VERSION 5.8 ;
BUSBITCHARS "[]" ;
DIVIDERCHAR "/" ;
UNITS
    DATABASE MICRONS 1000 ;
END UNITS

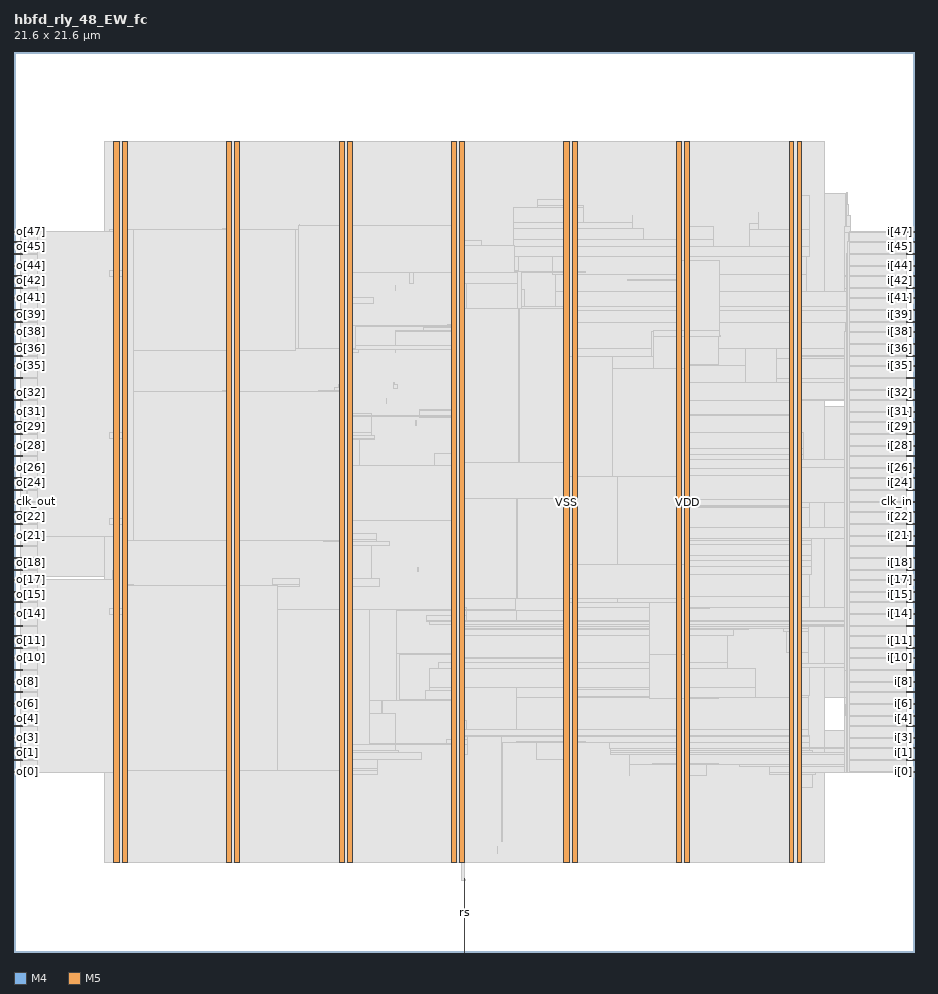
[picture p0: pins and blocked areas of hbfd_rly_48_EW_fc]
MACRO hbfd_rly_48_EW_fc
  FOREIGN hbfd_rly_48_EW_fc 0 0 ;
  CLASS BLOCK ;
  SIZE 21.6 BY 21.6 ;
  PIN clk_in
    DIRECTION INPUT ;
    USE SIGNAL ;
    PORT
      LAYER M4 ;
        RECT  21.408 10.8 21.6 10.824 ;
    END
  END clk_in
  PIN clk_out
    DIRECTION OUTPUT ;
    USE SIGNAL ;
    PORT
      LAYER M4 ;
        RECT  0 10.8 0.192 10.824 ;
    END
  END clk_out
  PIN i[0]
    DIRECTION INPUT ;
    USE SIGNAL ;
    PORT
      LAYER M4 ;
        RECT  21.408 4.32 21.6 4.344 ;
    END
  END i[0]
  PIN i[10]
    DIRECTION INPUT ;
    USE SIGNAL ;
    PORT
      LAYER M4 ;
        RECT  21.408 7.056 21.6 7.08 ;
    END
  END i[10]
  PIN i[11]
    DIRECTION INPUT ;
    USE SIGNAL ;
    PORT
      LAYER M4 ;
        RECT  21.408 7.296 21.6 7.32 ;
    END
  END i[11]
  PIN i[12]
    DIRECTION INPUT ;
    USE SIGNAL ;
    PORT
      LAYER M4 ;
        RECT  21.408 7.584 21.6 7.608 ;
    END
  END i[12]
  PIN i[13]
    DIRECTION INPUT ;
    USE SIGNAL ;
    PORT
      LAYER M4 ;
        RECT  21.408 7.824 21.6 7.848 ;
    END
  END i[13]
  PIN i[14]
    DIRECTION INPUT ;
    USE SIGNAL ;
    PORT
      LAYER M4 ;
        RECT  21.408 8.112 21.6 8.136 ;
    END
  END i[14]
  PIN i[15]
    DIRECTION INPUT ;
    USE SIGNAL ;
    PORT
      LAYER M4 ;
        RECT  21.408 8.4 21.6 8.424 ;
    END
  END i[15]
  PIN i[16]
    DIRECTION INPUT ;
    USE SIGNAL ;
    PORT
      LAYER M4 ;
        RECT  21.408 8.64 21.6 8.664 ;
    END
  END i[16]
  PIN i[17]
    DIRECTION INPUT ;
    USE SIGNAL ;
    PORT
      LAYER M4 ;
        RECT  21.408 8.928 21.6 8.952 ;
    END
  END i[17]
  PIN i[18]
    DIRECTION INPUT ;
    USE SIGNAL ;
    PORT
      LAYER M4 ;
        RECT  21.408 9.168 21.6 9.192 ;
    END
  END i[18]
  PIN i[19]
    DIRECTION INPUT ;
    USE SIGNAL ;
    PORT
      LAYER M4 ;
        RECT  21.408 9.456 21.6 9.48 ;
    END
  END i[19]
  PIN i[1]
    DIRECTION INPUT ;
    USE SIGNAL ;
    PORT
      LAYER M4 ;
        RECT  21.408 4.608 21.6 4.632 ;
    END
  END i[1]
  PIN i[20]
    DIRECTION INPUT ;
    USE SIGNAL ;
    PORT
      LAYER M4 ;
        RECT  21.408 9.744 21.6 9.768 ;
    END
  END i[20]
  PIN i[21]
    DIRECTION INPUT ;
    USE SIGNAL ;
    PORT
      LAYER M4 ;
        RECT  21.408 9.984 21.6 10.008 ;
    END
  END i[21]
  PIN i[22]
    DIRECTION INPUT ;
    USE SIGNAL ;
    PORT
      LAYER M4 ;
        RECT  21.408 10.272 21.6 10.296 ;
    END
  END i[22]
  PIN i[23]
    DIRECTION INPUT ;
    USE SIGNAL ;
    PORT
      LAYER M4 ;
        RECT  21.408 10.56 21.6 10.584 ;
    END
  END i[23]
  PIN i[24]
    DIRECTION INPUT ;
    USE SIGNAL ;
    PORT
      LAYER M4 ;
        RECT  21.408 11.088 21.6 11.112 ;
    END
  END i[24]
  PIN i[25]
    DIRECTION INPUT ;
    USE SIGNAL ;
    PORT
      LAYER M4 ;
        RECT  21.408 11.376 21.6 11.4 ;
    END
  END i[25]
  PIN i[26]
    DIRECTION INPUT ;
    USE SIGNAL ;
    PORT
      LAYER M4 ;
        RECT  21.408 11.616 21.6 11.64 ;
    END
  END i[26]
  PIN i[27]
    DIRECTION INPUT ;
    USE SIGNAL ;
    PORT
      LAYER M4 ;
        RECT  21.408 11.904 21.6 11.928 ;
    END
  END i[27]
  PIN i[28]
    DIRECTION INPUT ;
    USE SIGNAL ;
    PORT
      LAYER M4 ;
        RECT  21.408 12.144 21.6 12.168 ;
    END
  END i[28]
  PIN i[29]
    DIRECTION INPUT ;
    USE SIGNAL ;
    PORT
      LAYER M4 ;
        RECT  21.408 12.432 21.6 12.456 ;
    END
  END i[29]
  PIN i[2]
    DIRECTION INPUT ;
    USE SIGNAL ;
    PORT
      LAYER M4 ;
        RECT  21.408 4.896 21.6 4.92 ;
    END
  END i[2]
  PIN i[30]
    DIRECTION INPUT ;
    USE SIGNAL ;
    PORT
      LAYER M4 ;
        RECT  21.408 12.72 21.6 12.744 ;
    END
  END i[30]
  PIN i[31]
    DIRECTION INPUT ;
    USE SIGNAL ;
    PORT
      LAYER M4 ;
        RECT  21.408 12.96 21.6 12.984 ;
    END
  END i[31]
  PIN i[32]
    DIRECTION INPUT ;
    USE SIGNAL ;
    PORT
      LAYER M4 ;
        RECT  21.408 13.248 21.6 13.272 ;
    END
  END i[32]
  PIN i[33]
    DIRECTION INPUT ;
    USE SIGNAL ;
    PORT
      LAYER M4 ;
        RECT  21.408 13.488 21.6 13.512 ;
    END
  END i[33]
  PIN i[34]
    DIRECTION INPUT ;
    USE SIGNAL ;
    PORT
      LAYER M4 ;
        RECT  21.408 13.776 21.6 13.8 ;
    END
  END i[34]
  PIN i[35]
    DIRECTION INPUT ;
    USE SIGNAL ;
    PORT
      LAYER M4 ;
        RECT  21.408 14.064 21.6 14.088 ;
    END
  END i[35]
  PIN i[36]
    DIRECTION INPUT ;
    USE SIGNAL ;
    PORT
      LAYER M4 ;
        RECT  21.408 14.304 21.6 14.328 ;
    END
  END i[36]
  PIN i[37]
    DIRECTION INPUT ;
    USE SIGNAL ;
    PORT
      LAYER M4 ;
        RECT  21.408 14.592 21.6 14.616 ;
    END
  END i[37]
  PIN i[38]
    DIRECTION INPUT ;
    USE SIGNAL ;
    PORT
      LAYER M4 ;
        RECT  21.408 14.88 21.6 14.904 ;
    END
  END i[38]
  PIN i[39]
    DIRECTION INPUT ;
    USE SIGNAL ;
    PORT
      LAYER M4 ;
        RECT  21.408 15.12 21.6 15.144 ;
    END
  END i[39]
  PIN i[3]
    DIRECTION INPUT ;
    USE SIGNAL ;
    PORT
      LAYER M4 ;
        RECT  21.408 5.136 21.6 5.16 ;
    END
  END i[3]
  PIN i[40]
    DIRECTION INPUT ;
    USE SIGNAL ;
    PORT
      LAYER M4 ;
        RECT  21.408 15.408 21.6 15.432 ;
    END
  END i[40]
  PIN i[41]
    DIRECTION INPUT ;
    USE SIGNAL ;
    PORT
      LAYER M4 ;
        RECT  21.408 15.696 21.6 15.72 ;
    END
  END i[41]
  PIN i[42]
    DIRECTION INPUT ;
    USE SIGNAL ;
    PORT
      LAYER M4 ;
        RECT  21.408 15.936 21.6 15.96 ;
    END
  END i[42]
  PIN i[43]
    DIRECTION INPUT ;
    USE SIGNAL ;
    PORT
      LAYER M4 ;
        RECT  21.408 16.224 21.6 16.248 ;
    END
  END i[43]
  PIN i[44]
    DIRECTION INPUT ;
    USE SIGNAL ;
    PORT
      LAYER M4 ;
        RECT  21.408 16.464 21.6 16.488 ;
    END
  END i[44]
  PIN i[45]
    DIRECTION INPUT ;
    USE SIGNAL ;
    PORT
      LAYER M4 ;
        RECT  21.408 16.752 21.6 16.776 ;
    END
  END i[45]
  PIN i[46]
    DIRECTION INPUT ;
    USE SIGNAL ;
    PORT
      LAYER M4 ;
        RECT  21.408 17.04 21.6 17.064 ;
    END
  END i[46]
  PIN i[47]
    DIRECTION INPUT ;
    USE SIGNAL ;
    PORT
      LAYER M4 ;
        RECT  21.408 17.28 21.6 17.304 ;
    END
  END i[47]
  PIN i[4]
    DIRECTION INPUT ;
    USE SIGNAL ;
    PORT
      LAYER M4 ;
        RECT  21.408 5.424 21.6 5.448 ;
    END
  END i[4]
  PIN i[5]
    DIRECTION INPUT ;
    USE SIGNAL ;
    PORT
      LAYER M4 ;
        RECT  21.408 5.664 21.6 5.688 ;
    END
  END i[5]
  PIN i[6]
    DIRECTION INPUT ;
    USE SIGNAL ;
    PORT
      LAYER M4 ;
        RECT  21.408 5.952 21.6 5.976 ;
    END
  END i[6]
  PIN i[7]
    DIRECTION INPUT ;
    USE SIGNAL ;
    PORT
      LAYER M4 ;
        RECT  21.408 6.24 21.6 6.264 ;
    END
  END i[7]
  PIN i[8]
    DIRECTION INPUT ;
    USE SIGNAL ;
    PORT
      LAYER M4 ;
        RECT  21.408 6.48 21.6 6.504 ;
    END
  END i[8]
  PIN i[9]
    DIRECTION INPUT ;
    USE SIGNAL ;
    PORT
      LAYER M4 ;
        RECT  21.408 6.768 21.6 6.792 ;
    END
  END i[9]
  PIN o[0]
    DIRECTION OUTPUT ;
    USE SIGNAL ;
    PORT
      LAYER M4 ;
        RECT  0 4.32 0.192 4.344 ;
    END
  END o[0]
  PIN o[10]
    DIRECTION OUTPUT ;
    USE SIGNAL ;
    PORT
      LAYER M4 ;
        RECT  0 7.056 0.192 7.08 ;
    END
  END o[10]
  PIN o[11]
    DIRECTION OUTPUT ;
    USE SIGNAL ;
    PORT
      LAYER M4 ;
        RECT  0 7.296 0.192 7.32 ;
    END
  END o[11]
  PIN o[12]
    DIRECTION OUTPUT ;
    USE SIGNAL ;
    PORT
      LAYER M4 ;
        RECT  0 7.584 0.192 7.608 ;
    END
  END o[12]
  PIN o[13]
    DIRECTION OUTPUT ;
    USE SIGNAL ;
    PORT
      LAYER M4 ;
        RECT  0 7.824 0.192 7.848 ;
    END
  END o[13]
  PIN o[14]
    DIRECTION OUTPUT ;
    USE SIGNAL ;
    PORT
      LAYER M4 ;
        RECT  0 8.112 0.192 8.136 ;
    END
  END o[14]
  PIN o[15]
    DIRECTION OUTPUT ;
    USE SIGNAL ;
    PORT
      LAYER M4 ;
        RECT  0 8.4 0.192 8.424 ;
    END
  END o[15]
  PIN o[16]
    DIRECTION OUTPUT ;
    USE SIGNAL ;
    PORT
      LAYER M4 ;
        RECT  0 8.64 0.192 8.664 ;
    END
  END o[16]
  PIN o[17]
    DIRECTION OUTPUT ;
    USE SIGNAL ;
    PORT
      LAYER M4 ;
        RECT  0 8.928 0.192 8.952 ;
    END
  END o[17]
  PIN o[18]
    DIRECTION OUTPUT ;
    USE SIGNAL ;
    PORT
      LAYER M4 ;
        RECT  0 9.168 0.192 9.192 ;
    END
  END o[18]
  PIN o[19]
    DIRECTION OUTPUT ;
    USE SIGNAL ;
    PORT
      LAYER M4 ;
        RECT  0 9.456 0.192 9.48 ;
    END
  END o[19]
  PIN o[1]
    DIRECTION OUTPUT ;
    USE SIGNAL ;
    PORT
      LAYER M4 ;
        RECT  0 4.608 0.192 4.632 ;
    END
  END o[1]
  PIN o[20]
    DIRECTION OUTPUT ;
    USE SIGNAL ;
    PORT
      LAYER M4 ;
        RECT  0 9.744 0.192 9.768 ;
    END
  END o[20]
  PIN o[21]
    DIRECTION OUTPUT ;
    USE SIGNAL ;
    PORT
      LAYER M4 ;
        RECT  0 9.984 0.192 10.008 ;
    END
  END o[21]
  PIN o[22]
    DIRECTION OUTPUT ;
    USE SIGNAL ;
    PORT
      LAYER M4 ;
        RECT  0 10.272 0.192 10.296 ;
    END
  END o[22]
  PIN o[23]
    DIRECTION OUTPUT ;
    USE SIGNAL ;
    PORT
      LAYER M4 ;
        RECT  0 10.56 0.192 10.584 ;
    END
  END o[23]
  PIN o[24]
    DIRECTION OUTPUT ;
    USE SIGNAL ;
    PORT
      LAYER M4 ;
        RECT  0 11.088 0.192 11.112 ;
    END
  END o[24]
  PIN o[25]
    DIRECTION OUTPUT ;
    USE SIGNAL ;
    PORT
      LAYER M4 ;
        RECT  0 11.376 0.192 11.4 ;
    END
  END o[25]
  PIN o[26]
    DIRECTION OUTPUT ;
    USE SIGNAL ;
    PORT
      LAYER M4 ;
        RECT  0 11.616 0.192 11.64 ;
    END
  END o[26]
  PIN o[27]
    DIRECTION OUTPUT ;
    USE SIGNAL ;
    PORT
      LAYER M4 ;
        RECT  0 11.904 0.192 11.928 ;
    END
  END o[27]
  PIN o[28]
    DIRECTION OUTPUT ;
    USE SIGNAL ;
    PORT
      LAYER M4 ;
        RECT  0 12.144 0.192 12.168 ;
    END
  END o[28]
  PIN o[29]
    DIRECTION OUTPUT ;
    USE SIGNAL ;
    PORT
      LAYER M4 ;
        RECT  0 12.432 0.192 12.456 ;
    END
  END o[29]
  PIN o[2]
    DIRECTION OUTPUT ;
    USE SIGNAL ;
    PORT
      LAYER M4 ;
        RECT  0 4.896 0.192 4.92 ;
    END
  END o[2]
  PIN o[30]
    DIRECTION OUTPUT ;
    USE SIGNAL ;
    PORT
      LAYER M4 ;
        RECT  0 12.72 0.192 12.744 ;
    END
  END o[30]
  PIN o[31]
    DIRECTION OUTPUT ;
    USE SIGNAL ;
    PORT
      LAYER M4 ;
        RECT  0 12.96 0.192 12.984 ;
    END
  END o[31]
  PIN o[32]
    DIRECTION OUTPUT ;
    USE SIGNAL ;
    PORT
      LAYER M4 ;
        RECT  0 13.248 0.192 13.272 ;
    END
  END o[32]
  PIN o[33]
    DIRECTION OUTPUT ;
    USE SIGNAL ;
    PORT
      LAYER M4 ;
        RECT  0 13.488 0.192 13.512 ;
    END
  END o[33]
  PIN o[34]
    DIRECTION OUTPUT ;
    USE SIGNAL ;
    PORT
      LAYER M4 ;
        RECT  0 13.776 0.192 13.8 ;
    END
  END o[34]
  PIN o[35]
    DIRECTION OUTPUT ;
    USE SIGNAL ;
    PORT
      LAYER M4 ;
        RECT  0 14.064 0.192 14.088 ;
    END
  END o[35]
  PIN o[36]
    DIRECTION OUTPUT ;
    USE SIGNAL ;
    PORT
      LAYER M4 ;
        RECT  0 14.304 0.192 14.328 ;
    END
  END o[36]
  PIN o[37]
    DIRECTION OUTPUT ;
    USE SIGNAL ;
    PORT
      LAYER M4 ;
        RECT  0 14.592 0.192 14.616 ;
    END
  END o[37]
  PIN o[38]
    DIRECTION OUTPUT ;
    USE SIGNAL ;
    PORT
      LAYER M4 ;
        RECT  0 14.88 0.192 14.904 ;
    END
  END o[38]
  PIN o[39]
    DIRECTION OUTPUT ;
    USE SIGNAL ;
    PORT
      LAYER M4 ;
        RECT  0 15.12 0.192 15.144 ;
    END
  END o[39]
  PIN o[3]
    DIRECTION OUTPUT ;
    USE SIGNAL ;
    PORT
      LAYER M4 ;
        RECT  0 5.136 0.192 5.16 ;
    END
  END o[3]
  PIN o[40]
    DIRECTION OUTPUT ;
    USE SIGNAL ;
    PORT
      LAYER M4 ;
        RECT  0 15.408 0.192 15.432 ;
    END
  END o[40]
  PIN o[41]
    DIRECTION OUTPUT ;
    USE SIGNAL ;
    PORT
      LAYER M4 ;
        RECT  0 15.696 0.192 15.72 ;
    END
  END o[41]
  PIN o[42]
    DIRECTION OUTPUT ;
    USE SIGNAL ;
    PORT
      LAYER M4 ;
        RECT  0 15.936 0.192 15.96 ;
    END
  END o[42]
  PIN o[43]
    DIRECTION OUTPUT ;
    USE SIGNAL ;
    PORT
      LAYER M4 ;
        RECT  0 16.224 0.192 16.248 ;
    END
  END o[43]
  PIN o[44]
    DIRECTION OUTPUT ;
    USE SIGNAL ;
    PORT
      LAYER M4 ;
        RECT  0 16.464 0.192 16.488 ;
    END
  END o[44]
  PIN o[45]
    DIRECTION OUTPUT ;
    USE SIGNAL ;
    PORT
      LAYER M4 ;
        RECT  0 16.752 0.192 16.776 ;
    END
  END o[45]
  PIN o[46]
    DIRECTION OUTPUT ;
    USE SIGNAL ;
    PORT
      LAYER M4 ;
        RECT  0 17.04 0.192 17.064 ;
    END
  END o[46]
  PIN o[47]
    DIRECTION OUTPUT ;
    USE SIGNAL ;
    PORT
      LAYER M4 ;
        RECT  0 17.28 0.192 17.304 ;
    END
  END o[47]
  PIN o[4]
    DIRECTION OUTPUT ;
    USE SIGNAL ;
    PORT
      LAYER M4 ;
        RECT  0 5.424 0.192 5.448 ;
    END
  END o[4]
  PIN o[5]
    DIRECTION OUTPUT ;
    USE SIGNAL ;
    PORT
      LAYER M4 ;
        RECT  0 5.664 0.192 5.688 ;
    END
  END o[5]
  PIN o[6]
    DIRECTION OUTPUT ;
    USE SIGNAL ;
    PORT
      LAYER M4 ;
        RECT  0 5.952 0.192 5.976 ;
    END
  END o[6]
  PIN o[7]
    DIRECTION OUTPUT ;
    USE SIGNAL ;
    PORT
      LAYER M4 ;
        RECT  0 6.24 0.192 6.264 ;
    END
  END o[7]
  PIN o[8]
    DIRECTION OUTPUT ;
    USE SIGNAL ;
    PORT
      LAYER M4 ;
        RECT  0 6.48 0.192 6.504 ;
    END
  END o[8]
  PIN o[9]
    DIRECTION OUTPUT ;
    USE SIGNAL ;
    PORT
      LAYER M4 ;
        RECT  0 6.768 0.192 6.792 ;
    END
  END o[9]
  PIN rs
    DIRECTION INPUT ;
    USE SIGNAL ;
    PORT
      LAYER M5 ;
        RECT  10.8 0 10.824 0.192 ;
    END
    PORT
      LAYER M5 ;
        RECT  10.8 0.144 10.824 1.763 ;
    END
  END rs
  PIN VDD
    DIRECTION INOUT ;
    USE POWER ;
    PORT
      LAYER M5 ;
        RECT  18.792 2.151 18.912 19.449 ;
        RECT  16.092 2.151 16.212 19.449 ;
        RECT  13.392 2.151 13.512 19.449 ;
        RECT  10.692 2.151 10.812 19.449 ;
        RECT  7.992 2.151 8.112 19.449 ;
        RECT  5.292 2.151 5.412 19.449 ;
        RECT  2.592 2.151 2.712 19.449 ;
    END
  END VDD
  PIN VSS
    DIRECTION INOUT ;
    USE GROUND ;
    PORT
      LAYER M5 ;
        RECT  18.6 2.137 18.72 19.463 ;
        RECT  15.9 2.137 16.02 19.463 ;
        RECT  13.2 2.137 13.32 19.463 ;
        RECT  10.5 2.137 10.62 19.463 ;
        RECT  7.8 2.137 7.92 19.463 ;
        RECT  5.1 2.137 5.22 19.463 ;
        RECT  2.4 2.137 2.52 19.463 ;
    END
  END VSS
  # OT_OBS_CLOSED layer=M5 d_um=1.536 added=10
  OBS
    LAYER RVTN ;
     RECT  2.16 2.16 19.44 2.295 ;
     RECT  2.16 2.565 19.44 2.835 ;
     RECT  2.16 3.105 19.44 3.375 ;
     RECT  2.16 3.645 19.44 3.915 ;
     RECT  2.16 4.185 19.44 4.455 ;
     RECT  2.16 4.725 19.44 4.995 ;
     RECT  2.16 5.265 19.44 5.535 ;
     RECT  2.16 5.805 19.44 6.075 ;
     RECT  2.16 6.345 19.44 6.615 ;
     RECT  2.16 6.885 19.44 7.155 ;
     RECT  2.16 7.425 19.44 7.695 ;
     RECT  2.16 7.965 19.44 8.235 ;
     RECT  2.16 8.505 19.44 8.775 ;
     RECT  2.16 9.045 19.44 9.315 ;
     RECT  2.16 9.585 19.44 9.855 ;
     RECT  2.16 10.125 19.44 10.395 ;
     RECT  2.16 10.665 19.44 10.935 ;
     RECT  2.16 11.205 19.44 11.475 ;
     RECT  2.16 11.745 19.44 12.015 ;
     RECT  2.16 12.285 19.44 12.555 ;
     RECT  2.16 12.825 19.44 13.095 ;
     RECT  2.16 13.365 19.44 13.635 ;
     RECT  2.16 13.905 19.44 14.175 ;
     RECT  2.16 14.445 19.44 14.715 ;
     RECT  2.16 14.985 19.44 15.255 ;
     RECT  2.16 15.525 19.44 15.795 ;
     RECT  2.16 16.065 19.44 16.335 ;
     RECT  2.16 16.605 19.44 16.875 ;
     RECT  2.16 17.145 19.44 17.415 ;
     RECT  2.16 17.685 19.44 17.955 ;
     RECT  2.16 18.225 19.44 18.495 ;
     RECT  2.16 18.765 19.44 19.035 ;
     RECT  2.16 19.305 19.44 19.44 ;
    LAYER RVTP ;
     RECT  2.16 2.295 19.44 2.565 ;
     RECT  2.16 2.835 19.44 3.105 ;
     RECT  2.16 3.375 19.44 3.645 ;
     RECT  2.16 3.915 19.44 4.185 ;
     RECT  2.16 4.455 19.44 4.725 ;
     RECT  2.16 4.995 19.44 5.265 ;
     RECT  2.16 5.535 19.44 5.805 ;
     RECT  2.16 6.075 19.44 6.345 ;
     RECT  2.16 6.615 19.44 6.885 ;
     RECT  2.16 7.155 19.44 7.425 ;
     RECT  2.16 7.695 19.44 7.965 ;
     RECT  2.16 8.235 19.44 8.505 ;
     RECT  2.16 8.775 19.44 9.045 ;
     RECT  2.16 9.315 19.44 9.585 ;
     RECT  2.16 9.855 19.44 10.125 ;
     RECT  2.16 10.395 19.44 10.665 ;
     RECT  2.16 10.935 19.44 11.205 ;
     RECT  2.16 11.475 19.44 11.745 ;
     RECT  2.16 12.015 19.44 12.285 ;
     RECT  2.16 12.555 19.44 12.825 ;
     RECT  2.16 13.095 19.44 13.365 ;
     RECT  2.16 13.635 19.44 13.905 ;
     RECT  2.16 14.175 19.44 14.445 ;
     RECT  2.16 14.715 19.44 14.985 ;
     RECT  2.16 15.255 19.44 15.525 ;
     RECT  2.16 15.795 19.44 16.065 ;
     RECT  2.16 16.335 19.44 16.605 ;
     RECT  2.16 16.875 19.44 17.145 ;
     RECT  2.16 17.415 19.44 17.685 ;
     RECT  2.16 17.955 19.44 18.225 ;
     RECT  2.16 18.495 19.44 18.765 ;
     RECT  2.16 19.035 19.44 19.305 ;
    LAYER M1 ;
     RECT  2.16 2.151 19.44 19.449 ;
    LAYER M2 ;
     RECT  0.211 16.038 0.247 16.056 ;
     RECT  0.211 9.486 0.535 10.314 ;
     RECT  0.211 11.646 0.535 11.664 ;
     RECT  0.211 13.266 0.535 13.932 ;
     RECT  0.211 5.166 2.16 5.724 ;
     RECT  0.211 7.236 2.16 8.262 ;
     RECT  0.535 9.018 2.16 10.314 ;
     RECT  0.535 11.25 2.16 12.384 ;
     RECT  0.535 13.266 2.16 15.246 ;
     RECT  0.247 16.038 2.16 16.794 ;
     RECT  2.16 2.151 19.44 19.449 ;
     RECT  19.44 4.428 19.967 5.328 ;
     RECT  19.44 6.12 19.967 13.086 ;
     RECT  19.44 13.878 19.967 18.216 ;
     RECT  19.967 9.09 20.003 9.648 ;
     RECT  19.967 11.826 20.003 11.844 ;
     RECT  19.967 14.22 20.003 14.238 ;
     RECT  19.967 15.3 20.003 16.668 ;
     RECT  19.967 17.658 20.003 18.216 ;
     RECT  19.967 10.908 20.039 10.926 ;
     RECT  20.003 16.308 20.039 16.326 ;
     RECT  20.003 17.658 20.039 17.946 ;
     RECT  20.039 17.658 20.075 17.676 ;
     RECT  19.967 5.04 20.543 5.058 ;
     RECT  19.967 6.12 20.543 6.84 ;
     RECT  20.003 9.09 20.543 9.108 ;
    LAYER M3 ;
     RECT  10.8 1.723 10.818 2.143 ;
     RECT  10.515 2.143 10.818 2.255 ;
     RECT  2.415 2.143 2.505 2.413 ;
     RECT  5.115 2.143 5.205 2.413 ;
     RECT  7.815 2.143 7.905 2.413 ;
     RECT  13.215 2.143 13.305 2.413 ;
     RECT  15.915 2.143 16.005 2.413 ;
     RECT  18.615 2.143 18.705 2.413 ;
     RECT  11.592 2.371 11.61 2.525 ;
     RECT  18.615 2.413 18.897 3.955 ;
     RECT  15.915 2.413 16.197 4.225 ;
     RECT  7.815 2.413 8.097 4.261 ;
     RECT  18.615 3.955 19.17 4.261 ;
     RECT  2.415 2.413 2.697 4.315 ;
     RECT  18.144 4.261 19.242 4.315 ;
     RECT  5.115 2.413 5.397 4.351 ;
     RECT  7.815 4.261 8.73 4.351 ;
     RECT  7.704 4.351 8.73 4.397 ;
     RECT  18.144 4.315 19.962 4.459 ;
     RECT  15.915 4.225 16.614 4.495 ;
     RECT  17.424 4.459 19.962 4.495 ;
     RECT  14.76 4.225 14.778 4.507 ;
     RECT  15.915 4.495 19.962 4.507 ;
     RECT  7.815 4.397 8.73 4.621 ;
     RECT  13.215 2.413 13.497 4.621 ;
     RECT  10.515 2.255 10.797 4.729 ;
     RECT  14.76 4.507 19.962 4.729 ;
     RECT  7.815 4.621 9.774 4.793 ;
     RECT  14.328 4.729 19.962 4.793 ;
     RECT  7.815 4.793 9.234 4.829 ;
     RECT  14.328 4.793 19.17 4.829 ;
     RECT  14.328 4.829 19.098 4.891 ;
     RECT  2.304 4.315 2.697 4.928 ;
     RECT  5.004 4.351 5.397 4.928 ;
     RECT  10.515 4.729 10.89 4.987 ;
     RECT  6.84 4.891 6.858 5.021 ;
     RECT  12.528 4.621 13.497 5.029 ;
     RECT  14.292 4.891 19.098 5.029 ;
     RECT  11.7 2.641 11.718 5.032 ;
     RECT  12.528 5.029 19.098 5.032 ;
     RECT  19.944 4.793 19.962 5.035 ;
     RECT  10.368 4.987 10.89 5.099 ;
     RECT  10.515 5.099 10.89 5.161 ;
     RECT  11.7 5.032 19.098 5.161 ;
     RECT  19.944 5.035 20.538 5.165 ;
     RECT  10.515 5.161 19.098 5.189 ;
     RECT  10.515 5.189 19.062 5.333 ;
     RECT  0.216 5.131 0.234 5.563 ;
     RECT  10.515 5.333 10.854 5.567 ;
     RECT  0.216 5.563 0.27 5.693 ;
     RECT  0.216 5.693 0.234 5.729 ;
     RECT  7.815 4.829 9.162 5.729 ;
     RECT  7.056 5.701 7.074 5.809 ;
     RECT  6.768 5.809 7.074 5.873 ;
     RECT  6.768 5.873 6.858 5.909 ;
     RECT  2.415 4.928 2.697 5.947 ;
     RECT  19.944 5.165 19.962 5.947 ;
     RECT  10.515 5.567 10.797 6.043 ;
     RECT  12.06 5.333 19.062 6.107 ;
     RECT  19.944 5.947 19.998 6.115 ;
     RECT  2.304 5.947 2.697 6.139 ;
     RECT  5.115 4.928 5.397 6.139 ;
     RECT  18.615 6.107 19.062 6.151 ;
     RECT  6.84 5.909 6.858 6.173 ;
     RECT  5.115 6.139 5.49 6.179 ;
     RECT  9.864 6.043 10.797 6.269 ;
     RECT  9.972 6.269 10.797 6.349 ;
     RECT  12.06 6.107 17.802 6.349 ;
     RECT  2.304 6.139 2.79 6.523 ;
     RECT  7.815 5.729 8.097 6.619 ;
     RECT  2.304 6.523 2.862 6.653 ;
     RECT  7.704 6.619 8.097 6.655 ;
     RECT  8.82 5.729 8.838 6.691 ;
     RECT  7.596 6.655 8.097 6.781 ;
     RECT  8.82 6.691 9.126 6.781 ;
     RECT  7.596 6.781 9.234 6.809 ;
     RECT  9.972 6.349 17.802 6.809 ;
     RECT  18.615 6.151 19.098 6.817 ;
     RECT  19.944 6.115 20.538 6.817 ;
     RECT  9.108 6.809 9.234 6.845 ;
     RECT  9.216 6.845 9.234 6.893 ;
     RECT  18.615 6.817 20.538 6.917 ;
     RECT  10.188 6.809 17.118 6.953 ;
     RECT  5.115 6.179 5.397 7.051 ;
     RECT  19.944 6.917 20.538 7.085 ;
     RECT  2.304 6.653 2.697 7.088 ;
     RECT  5.004 7.051 5.397 7.088 ;
     RECT  18.615 6.917 19.062 7.195 ;
     RECT  10.515 6.953 17.118 7.591 ;
     RECT  5.115 7.088 5.397 7.699 ;
     RECT  7.815 6.809 8.19 7.699 ;
     RECT  18.54 7.195 19.062 7.699 ;
     RECT  10.515 7.591 17.262 7.735 ;
     RECT  10.515 7.735 17.622 7.771 ;
     RECT  18.468 7.699 19.062 7.771 ;
     RECT  5.115 7.699 5.922 7.799 ;
     RECT  10.515 7.771 19.062 7.819 ;
     RECT  19.944 7.085 19.962 7.819 ;
     RECT  2.415 7.088 2.697 7.861 ;
     RECT  10.515 7.819 19.962 7.861 ;
     RECT  7.815 7.699 8.766 7.889 ;
     RECT  2.415 7.861 2.79 7.901 ;
     RECT  5.115 7.799 5.49 7.901 ;
     RECT  9.972 7.861 19.962 7.933 ;
     RECT  9.9 7.933 19.962 7.961 ;
     RECT  6.84 7.051 6.858 7.997 ;
     RECT  9.144 7.897 9.162 7.997 ;
     RECT  9.9 7.961 10.854 8.069 ;
     RECT  10.515 8.069 10.854 8.267 ;
     RECT  12.06 7.961 19.962 8.267 ;
     RECT  0.216 7.231 0.234 8.429 ;
     RECT  12.06 8.267 19.098 8.525 ;
     RECT  12.06 8.525 15.03 8.537 ;
     RECT  2.415 7.901 2.697 8.635 ;
     RECT  2.304 8.635 2.697 8.683 ;
     RECT  2.304 8.683 2.862 8.699 ;
     RECT  7.815 7.889 8.097 8.779 ;
     RECT  2.376 8.699 2.862 8.813 ;
     RECT  6.3 8.779 6.858 8.815 ;
     RECT  19.944 8.267 19.962 8.923 ;
     RECT  6.192 8.815 6.858 8.969 ;
     RECT  7.815 8.779 8.766 8.969 ;
     RECT  15.876 8.525 19.098 9.049 ;
     RECT  19.944 8.923 19.998 9.085 ;
     RECT  2.376 8.813 2.697 9.149 ;
     RECT  0.54 9.013 0.558 9.197 ;
     RECT  19.944 9.085 20.538 9.197 ;
     RECT  10.515 8.267 10.797 9.211 ;
     RECT  9.684 9.121 9.702 9.239 ;
     RECT  12.564 8.537 15.03 9.259 ;
     RECT  15.876 9.049 19.134 9.259 ;
     RECT  10.515 9.211 11.43 9.311 ;
     RECT  12.564 9.259 19.134 9.391 ;
     RECT  10.515 9.311 10.962 9.509 ;
     RECT  11.952 9.391 19.134 9.509 ;
     RECT  7.815 8.969 8.586 9.751 ;
     RECT  11.988 9.509 19.134 9.779 ;
     RECT  7.815 9.751 9.018 9.851 ;
     RECT  7.815 9.851 8.694 9.859 ;
     RECT  2.415 9.149 2.697 9.883 ;
     RECT  12.564 9.779 19.134 9.887 ;
     RECT  7.416 9.859 8.694 9.895 ;
     RECT  12.852 9.887 19.134 9.931 ;
     RECT  19.944 9.197 20.034 9.931 ;
     RECT  7.164 9.895 8.694 10.049 ;
     RECT  2.415 9.883 2.862 10.061 ;
     RECT  7.308 10.049 8.097 10.121 ;
     RECT  12.852 9.931 20.034 10.193 ;
     RECT  10.515 9.509 10.854 10.291 ;
     RECT  10.515 10.291 11.502 10.463 ;
     RECT  10.515 10.463 11.214 10.499 ;
     RECT  12.852 10.193 19.098 10.661 ;
     RECT  12.852 10.661 13.497 10.741 ;
     RECT  12.672 10.741 13.497 10.843 ;
     RECT  12.06 10.843 13.497 10.859 ;
     RECT  14.22 10.661 19.098 10.859 ;
     RECT  12.06 10.859 12.078 10.931 ;
     RECT  19.944 10.193 20.034 10.931 ;
     RECT  7.815 10.121 8.097 10.975 ;
     RECT  12.852 10.859 13.497 11.003 ;
     RECT  7.815 10.975 8.586 11.129 ;
     RECT  10.515 10.499 11.034 11.165 ;
     RECT  10.515 11.165 10.926 11.209 ;
     RECT  0.216 9.451 0.234 11.245 ;
     RECT  7.815 11.129 8.478 11.309 ;
     RECT  12.888 11.003 13.497 11.443 ;
     RECT  14.22 10.859 19.062 11.443 ;
     RECT  10.224 11.209 10.926 11.515 ;
     RECT  12.888 11.443 19.062 11.611 ;
     RECT  19.944 10.931 19.962 11.611 ;
     RECT  0.216 11.245 0.558 11.669 ;
     RECT  12.06 11.749 12.078 11.789 ;
     RECT  12.888 11.611 19.962 11.813 ;
     RECT  12.888 11.813 18.954 11.821 ;
     RECT  19.944 11.813 19.962 11.821 ;
     RECT  0.252 11.669 0.558 11.933 ;
     RECT  12.276 11.821 18.954 11.939 ;
     RECT  10.08 11.515 10.926 11.975 ;
     RECT  10.515 11.975 10.926 12.019 ;
     RECT  14.58 11.939 18.954 12.083 ;
     RECT  10.515 12.019 11.466 12.119 ;
     RECT  19.944 11.821 19.998 12.173 ;
     RECT  2.415 10.061 2.697 12.181 ;
     RECT  5.115 7.901 5.397 12.217 ;
     RECT  2.415 12.181 2.79 12.289 ;
     RECT  7.815 11.309 8.298 12.289 ;
     RECT  6.732 12.325 6.75 12.331 ;
     RECT  7.815 12.289 8.658 12.331 ;
     RECT  2.415 12.289 2.862 12.389 ;
     RECT  5.115 12.217 5.67 12.389 ;
     RECT  6.732 12.331 8.658 12.389 ;
     RECT  6.732 12.389 8.586 12.479 ;
     RECT  14.652 12.083 18.954 12.479 ;
     RECT  0.54 11.933 0.558 12.749 ;
     RECT  9.648 12.631 9.666 12.749 ;
     RECT  10.515 12.119 10.854 12.829 ;
     RECT  12.276 11.939 13.698 12.829 ;
     RECT  12.06 12.829 13.698 12.865 ;
     RECT  14.652 12.479 18.897 12.865 ;
     RECT  12.06 12.865 18.897 12.893 ;
     RECT  6.84 12.479 8.586 12.929 ;
     RECT  2.415 12.389 2.697 12.955 ;
     RECT  5.115 12.389 5.397 12.991 ;
     RECT  9.72 12.829 10.854 12.991 ;
     RECT  9.72 12.991 11.07 13.019 ;
     RECT  6.84 12.929 8.097 13.037 ;
     RECT  12.24 12.893 18.897 13.243 ;
     RECT  19.944 12.173 19.962 13.243 ;
     RECT  8.928 13.171 8.946 13.289 ;
     RECT  5.004 12.991 5.397 13.469 ;
     RECT  7.308 13.037 8.097 13.469 ;
     RECT  2.304 12.955 2.697 13.517 ;
     RECT  7.704 13.469 8.097 13.559 ;
     RECT  0.216 13.243 0.234 13.603 ;
     RECT  7.776 13.559 8.097 13.631 ;
     RECT  9.108 13.531 9.198 13.631 ;
     RECT  9.108 13.631 9.126 13.667 ;
     RECT  12.24 13.243 19.962 13.667 ;
     RECT  18.288 13.667 19.962 13.771 ;
     RECT  10.515 13.019 11.07 13.801 ;
     RECT  0.216 13.603 0.558 13.805 ;
     RECT  10.515 13.801 11.286 14.009 ;
     RECT  12.24 13.667 17.55 14.071 ;
     RECT  18.288 13.771 19.998 14.243 ;
     RECT  2.415 13.517 2.697 14.341 ;
     RECT  2.415 14.341 2.79 14.347 ;
     RECT  7.815 13.631 8.097 14.377 ;
     RECT  7.815 14.377 8.262 14.449 ;
     RECT  9.144 14.377 9.162 14.449 ;
     RECT  10.515 14.009 10.797 14.449 ;
     RECT  2.415 14.347 2.862 14.477 ;
     RECT  11.52 14.071 17.55 14.477 ;
     RECT  12.348 14.477 17.55 14.485 ;
     RECT  18.288 14.243 19.962 14.485 ;
     RECT  6.732 14.443 6.75 14.549 ;
     RECT  7.815 14.449 10.797 14.549 ;
     RECT  0.216 13.805 0.234 14.611 ;
     RECT  0.216 14.611 0.558 14.621 ;
     RECT  9.144 14.549 10.797 14.881 ;
     RECT  9.144 14.881 11.322 14.909 ;
     RECT  9.828 14.909 11.322 14.981 ;
     RECT  6.84 14.611 6.858 15.019 ;
     RECT  10.404 14.981 10.854 15.053 ;
     RECT  2.415 14.477 2.697 15.115 ;
     RECT  12.348 14.485 19.962 15.115 ;
     RECT  5.115 13.469 5.397 15.151 ;
     RECT  6.84 15.019 6.894 15.151 ;
     RECT  7.815 14.549 8.097 15.151 ;
     RECT  2.304 15.115 2.697 15.223 ;
     RECT  6.84 15.151 8.097 15.251 ;
     RECT  6.84 15.251 6.858 15.287 ;
     RECT  2.304 15.223 2.862 15.359 ;
     RECT  12.348 15.115 19.998 15.403 ;
     RECT  0.54 14.621 0.558 15.437 ;
     RECT  12.096 15.403 19.998 15.485 ;
     RECT  7.704 15.251 8.097 15.565 ;
     RECT  7.704 15.565 8.622 15.719 ;
     RECT  7.704 15.719 8.097 15.725 ;
     RECT  2.304 15.359 2.697 15.728 ;
     RECT  5.004 15.151 5.397 15.728 ;
     RECT  12.996 15.485 19.998 15.863 ;
     RECT  12.096 15.485 12.258 15.899 ;
     RECT  19.944 15.863 19.998 15.931 ;
     RECT  9.144 15.871 9.162 15.989 ;
     RECT  10.515 15.053 10.854 16.033 ;
     RECT  12.096 15.899 12.114 16.033 ;
     RECT  0.216 15.931 0.234 16.061 ;
     RECT  12.996 15.863 19.026 16.267 ;
     RECT  10.515 16.033 12.114 16.367 ;
     RECT  2.415 15.728 2.697 16.501 ;
     RECT  5.115 15.728 5.397 16.501 ;
     RECT  9.504 16.033 9.594 16.573 ;
     RECT  11.988 16.367 12.114 16.681 ;
     RECT  12.924 16.267 19.026 16.681 ;
     RECT  0.252 16.747 0.27 16.799 ;
     RECT  9.504 16.573 9.666 16.799 ;
     RECT  11.988 16.681 19.098 16.943 ;
     RECT  2.415 16.501 2.79 16.979 ;
     RECT  5.115 16.501 5.49 16.979 ;
     RECT  9.324 16.915 9.414 17.069 ;
     RECT  10.515 16.367 11.214 17.069 ;
     RECT  11.988 16.943 16.794 17.105 ;
     RECT  9.396 17.069 9.414 17.213 ;
     RECT  2.415 16.979 2.697 17.275 ;
     RECT  19.944 15.931 20.034 17.275 ;
     RECT  5.115 16.979 5.397 17.311 ;
     RECT  2.304 17.275 2.697 17.339 ;
     RECT  17.64 16.943 19.098 17.339 ;
     RECT  5.004 17.311 5.397 17.357 ;
     RECT  11.988 17.105 15.102 17.375 ;
     RECT  15.915 17.105 16.794 17.411 ;
     RECT  19.944 17.275 20.07 17.411 ;
     RECT  10.515 17.069 10.797 17.419 ;
     RECT  6.84 17.323 6.858 17.453 ;
     RECT  17.64 17.339 17.874 17.483 ;
     RECT  10.512 17.419 10.797 17.519 ;
     RECT  11.988 17.375 14.85 17.519 ;
     RECT  14.832 17.519 14.85 17.681 ;
     RECT  19.98 17.411 20.07 17.681 ;
     RECT  17.856 17.483 17.874 17.753 ;
     RECT  11.988 17.519 13.662 17.879 ;
     RECT  12.564 17.879 13.662 17.915 ;
     RECT  19.98 17.681 20.034 17.951 ;
     RECT  12.564 17.915 13.497 18.059 ;
     RECT  18.615 17.339 19.098 18.149 ;
     RECT  19.98 17.951 19.998 18.221 ;
     RECT  2.415 17.339 2.697 19.187 ;
     RECT  5.115 17.357 5.397 19.187 ;
     RECT  7.815 15.725 8.097 19.187 ;
     RECT  10.515 17.519 10.797 19.187 ;
     RECT  13.215 18.059 13.497 19.187 ;
     RECT  15.915 17.411 16.197 19.187 ;
     RECT  18.615 18.149 18.897 19.187 ;
     RECT  2.415 19.187 2.505 19.457 ;
     RECT  5.115 19.187 5.205 19.457 ;
     RECT  7.815 19.187 7.905 19.457 ;
     RECT  10.515 19.187 10.605 19.457 ;
     RECT  13.215 19.187 13.305 19.457 ;
     RECT  15.915 19.187 16.005 19.457 ;
     RECT  18.615 19.187 18.705 19.457 ;
    LAYER M4 ;
     RECT  0.192 4.32 0.569 4.344 ;
     RECT  0.156 4.344 0.569 4.608 ;
     RECT  0.192 4.608 0.569 4.632 ;
     RECT  0.156 4.632 0.569 4.896 ;
     RECT  0.192 4.896 0.569 4.92 ;
     RECT  0.156 4.92 0.569 5.136 ;
     RECT  0.192 5.136 0.569 5.16 ;
     RECT  0.156 5.16 0.569 5.424 ;
     RECT  0.192 5.424 0.569 5.448 ;
     RECT  0.156 5.448 0.569 5.664 ;
     RECT  0.192 5.664 0.569 5.688 ;
     RECT  0.156 5.688 0.569 5.952 ;
     RECT  0.192 5.952 0.569 5.976 ;
     RECT  0.156 5.976 0.569 6.24 ;
     RECT  0.192 6.24 0.569 6.264 ;
     RECT  0.156 6.264 0.569 6.48 ;
     RECT  0.192 6.48 0.569 6.504 ;
     RECT  0.156 6.504 0.569 6.768 ;
     RECT  0.192 6.768 0.569 6.792 ;
     RECT  0.156 6.792 0.569 7.056 ;
     RECT  0.192 7.056 0.569 7.08 ;
     RECT  0.156 7.08 0.569 7.296 ;
     RECT  0.192 7.296 0.569 7.32 ;
     RECT  0.156 7.32 0.569 7.584 ;
     RECT  0.192 7.584 0.569 7.608 ;
     RECT  0.156 7.608 0.569 7.824 ;
     RECT  0.192 7.824 0.569 7.848 ;
     RECT  0.156 7.848 0.569 8.112 ;
     RECT  0.192 8.112 0.569 8.136 ;
     RECT  0.156 8.136 0.569 8.4 ;
     RECT  0.192 8.4 0.569 8.424 ;
     RECT  0.156 8.424 0.569 8.64 ;
     RECT  0.192 8.64 0.569 8.664 ;
     RECT  0.156 8.664 0.569 8.928 ;
     RECT  0.192 8.928 0.569 8.952 ;
     RECT  0.156 8.952 0.569 9.168 ;
     RECT  0.192 9.168 0.569 9.192 ;
     RECT  0.156 9.192 0.569 9.456 ;
     RECT  0.192 9.456 0.569 9.48 ;
     RECT  0.156 9.48 0.569 9.744 ;
     RECT  0.192 9.744 0.569 9.768 ;
     RECT  0.156 9.768 0.569 9.984 ;
     RECT  0.192 9.984 0.569 10.008 ;
     RECT  0.156 10.008 0.569 10.272 ;
     RECT  0.192 10.272 0.569 10.296 ;
     RECT  0.156 10.296 0.569 10.56 ;
     RECT  0.192 10.56 0.569 10.584 ;
     RECT  0.156 10.584 0.569 10.8 ;
     RECT  0.192 10.8 0.569 10.824 ;
     RECT  0.156 10.824 0.569 11.088 ;
     RECT  0.192 11.088 0.569 11.112 ;
     RECT  0.156 11.112 0.569 11.376 ;
     RECT  0.192 11.376 0.569 11.4 ;
     RECT  0.156 11.4 0.569 11.616 ;
     RECT  0.192 11.616 0.569 11.64 ;
     RECT  0.156 11.64 0.569 11.904 ;
     RECT  0.192 11.904 0.569 11.928 ;
     RECT  0.156 11.928 0.569 12.144 ;
     RECT  0.192 12.144 0.569 12.168 ;
     RECT  0.156 12.168 0.569 12.432 ;
     RECT  0.192 12.432 0.569 12.456 ;
     RECT  0.156 12.456 0.569 12.72 ;
     RECT  0.192 12.72 0.569 12.744 ;
     RECT  0.156 12.744 0.569 12.96 ;
     RECT  0.192 12.96 0.569 12.984 ;
     RECT  0.156 12.984 0.569 13.248 ;
     RECT  0.192 13.248 0.569 13.272 ;
     RECT  0.156 13.272 0.569 13.488 ;
     RECT  0.192 13.488 0.569 13.512 ;
     RECT  0.156 13.512 0.569 13.776 ;
     RECT  0.192 13.776 0.569 13.8 ;
     RECT  0.156 13.8 0.569 14.064 ;
     RECT  0.192 14.064 0.569 14.088 ;
     RECT  0.156 14.088 0.569 14.304 ;
     RECT  0.192 14.304 0.569 14.328 ;
     RECT  0.156 14.328 0.569 14.592 ;
     RECT  0.192 14.592 0.569 14.616 ;
     RECT  0.156 14.616 0.569 14.88 ;
     RECT  0.192 14.88 0.569 14.904 ;
     RECT  0.156 14.904 0.569 15.12 ;
     RECT  0.192 15.12 0.569 15.144 ;
     RECT  0.156 15.144 0.569 15.408 ;
     RECT  0.192 15.408 0.569 15.432 ;
     RECT  0.156 15.432 0.569 15.696 ;
     RECT  0.192 15.696 0.569 15.72 ;
     RECT  0.156 15.72 0.569 15.936 ;
     RECT  0.192 15.936 0.569 15.96 ;
     RECT  0.156 15.96 0.569 16.224 ;
     RECT  0.192 16.224 0.569 16.248 ;
     RECT  0.156 16.248 0.569 16.464 ;
     RECT  0.192 16.464 0.569 16.488 ;
     RECT  0.156 16.488 0.569 16.752 ;
     RECT  0.192 16.752 0.569 16.776 ;
     RECT  0.156 16.776 0.569 17.04 ;
     RECT  0.192 17.04 0.569 17.064 ;
     RECT  0.156 17.064 0.569 17.28 ;
     RECT  0.192 17.28 0.569 17.304 ;
     RECT  0.569 4.32 2.408 8.952 ;
     RECT  0.569 9.984 2.408 17.304 ;
     RECT  2.408 2.148 2.512 19.452 ;
     RECT  2.512 2.418 2.704 19.182 ;
     RECT  2.704 9.888 2.873 17.352 ;
     RECT  2.704 4.368 5.108 8.808 ;
     RECT  2.873 9.888 5.108 13.464 ;
     RECT  2.873 14.448 5.108 17.352 ;
     RECT  5.108 2.148 5.212 19.452 ;
     RECT  5.212 2.418 5.404 19.182 ;
     RECT  5.404 4.368 6.329 8.808 ;
     RECT  5.404 14.448 6.761 17.352 ;
     RECT  6.761 14.496 6.829 17.352 ;
     RECT  6.329 4.368 7.808 8.232 ;
     RECT  5.404 9.888 7.808 13.464 ;
     RECT  6.829 14.496 7.808 17.448 ;
     RECT  7.808 2.148 7.912 19.452 ;
     RECT  7.912 2.418 8.104 19.182 ;
     RECT  8.104 14.496 8.201 15.048 ;
     RECT  8.104 4.992 8.525 8.232 ;
     RECT  8.525 6.048 9.173 8.232 ;
     RECT  9.173 6.048 9.245 7.176 ;
     RECT  8.525 4.992 10.508 5.016 ;
     RECT  9.245 6.048 10.508 6.072 ;
     RECT  9.245 7.152 10.508 7.176 ;
     RECT  9.173 8.208 10.508 8.232 ;
     RECT  8.104 10.368 10.508 11.688 ;
     RECT  8.104 12.864 10.508 12.888 ;
     RECT  8.201 15.024 10.508 15.048 ;
     RECT  8.104 16.32 10.508 17.448 ;
     RECT  10.508 2.148 10.612 19.452 ;
     RECT  10.612 2.148 10.748 19.182 ;
     RECT  10.748 1.728 10.804 19.182 ;
     RECT  10.804 1.728 10.835 1.752 ;
     RECT  10.804 10.368 10.865 11.544 ;
     RECT  10.804 16.32 12.017 16.968 ;
     RECT  10.804 8.208 12.037 8.232 ;
     RECT  10.865 10.368 12.037 11.448 ;
     RECT  12.037 9.6 12.044 11.448 ;
     RECT  12.017 16.32 12.085 16.344 ;
     RECT  12.044 9.6 12.124 11.784 ;
     RECT  12.124 10.368 12.131 11.784 ;
     RECT  12.044 12.864 12.131 12.888 ;
     RECT  10.804 14.208 12.131 14.232 ;
     RECT  12.085 15.408 12.169 16.344 ;
     RECT  12.049 5.04 13.208 5.064 ;
     RECT  10.804 7.056 13.208 7.08 ;
     RECT  12.037 8.208 13.208 8.52 ;
     RECT  12.131 10.368 13.208 11.448 ;
     RECT  12.169 16.32 13.208 16.344 ;
     RECT  13.208 2.148 13.312 19.452 ;
     RECT  13.312 2.418 13.504 19.182 ;
     RECT  13.504 5.04 13.709 5.064 ;
     RECT  13.504 16.32 13.709 16.344 ;
     RECT  13.504 8.4 13.737 11.448 ;
     RECT  13.737 9.456 13.756 11.448 ;
     RECT  13.756 10.368 14.249 11.448 ;
     RECT  14.249 10.368 14.321 11.4 ;
     RECT  14.321 10.704 14.529 11.4 ;
     RECT  14.529 10.704 14.861 10.824 ;
     RECT  13.504 6.144 15.253 6.312 ;
     RECT  13.737 8.4 15.26 8.424 ;
     RECT  13.504 14.16 15.288 14.28 ;
     RECT  15.288 14.016 15.289 14.28 ;
     RECT  15.26 8.4 15.397 9.288 ;
     RECT  15.325 4.512 15.908 4.536 ;
     RECT  15.253 6.096 15.908 7.128 ;
     RECT  15.397 8.256 15.908 9.288 ;
     RECT  14.861 10.704 15.908 10.728 ;
     RECT  14.821 12.672 15.908 12.696 ;
     RECT  15.289 14.016 15.908 14.904 ;
     RECT  14.713 16.128 15.908 16.152 ;
     RECT  15.908 2.148 16.012 19.452 ;
     RECT  16.012 2.418 16.204 19.182 ;
     RECT  16.204 8.256 16.697 8.28 ;
     RECT  16.204 4.512 16.913 4.536 ;
     RECT  16.204 6.096 16.913 6.12 ;
     RECT  16.204 14.112 16.913 14.808 ;
     RECT  16.204 15.792 16.931 16.584 ;
     RECT  16.913 14.784 16.957 14.808 ;
     RECT  16.204 10.704 18.608 10.728 ;
     RECT  18.608 2.148 18.712 19.452 ;
     RECT  18.712 2.418 18.904 19.182 ;
     RECT  18.904 4.896 19.933 4.92 ;
     RECT  18.904 7.824 19.933 7.848 ;
     RECT  18.904 10.8 19.933 11.64 ;
     RECT  18.904 13.248 19.933 13.272 ;
     RECT  18.904 14.304 19.933 14.328 ;
     RECT  19.933 4.32 19.969 5.688 ;
     RECT  19.933 6.768 19.969 14.904 ;
     RECT  19.933 16.224 19.969 16.248 ;
     RECT  19.969 4.32 20.005 16.776 ;
     RECT  20.005 4.32 20.041 17.064 ;
     RECT  20.041 4.32 21.408 4.344 ;
     RECT  20.041 4.344 21.42 4.608 ;
     RECT  20.041 4.608 21.408 4.632 ;
     RECT  20.041 4.632 21.42 4.896 ;
     RECT  20.041 4.896 21.408 4.92 ;
     RECT  20.041 4.92 21.42 5.136 ;
     RECT  20.041 5.136 21.408 5.16 ;
     RECT  20.041 5.16 21.42 5.424 ;
     RECT  20.041 5.424 21.408 5.448 ;
     RECT  20.041 5.448 21.42 5.664 ;
     RECT  20.041 5.664 21.408 5.688 ;
     RECT  20.041 5.688 21.42 5.952 ;
     RECT  20.041 5.952 21.408 5.976 ;
     RECT  20.041 5.976 21.42 6.24 ;
     RECT  20.041 6.24 21.408 6.264 ;
     RECT  20.041 6.264 21.42 6.48 ;
     RECT  20.041 6.48 21.408 6.504 ;
     RECT  20.041 6.504 21.42 6.768 ;
     RECT  20.041 6.768 21.408 6.792 ;
     RECT  20.041 6.792 21.42 7.056 ;
     RECT  20.041 7.056 21.408 7.08 ;
     RECT  20.041 7.08 21.42 7.296 ;
     RECT  20.041 7.296 21.408 7.32 ;
     RECT  20.041 7.32 21.42 7.584 ;
     RECT  20.041 7.584 21.408 7.608 ;
     RECT  20.041 7.608 21.42 7.824 ;
     RECT  20.041 7.824 21.408 7.848 ;
     RECT  20.041 7.848 21.42 8.112 ;
     RECT  20.041 8.112 21.408 8.136 ;
     RECT  20.041 8.136 21.42 8.4 ;
     RECT  20.041 8.4 21.408 8.424 ;
     RECT  20.041 8.424 21.42 8.64 ;
     RECT  20.041 8.64 21.408 8.664 ;
     RECT  20.041 8.664 21.42 8.928 ;
     RECT  20.041 8.928 21.408 8.952 ;
     RECT  20.041 8.952 21.42 9.168 ;
     RECT  20.041 9.168 21.408 9.192 ;
     RECT  20.041 9.192 21.42 9.456 ;
     RECT  20.041 9.456 21.408 9.48 ;
     RECT  20.041 9.48 21.42 9.744 ;
     RECT  20.041 9.744 21.408 9.768 ;
     RECT  20.041 9.768 21.42 9.984 ;
     RECT  20.041 9.984 21.408 10.008 ;
     RECT  20.041 10.008 21.42 10.272 ;
     RECT  20.041 10.272 21.408 10.296 ;
     RECT  20.041 10.296 21.42 10.56 ;
     RECT  20.041 10.56 21.408 10.584 ;
     RECT  20.041 10.584 21.42 10.8 ;
     RECT  20.041 10.8 21.408 10.824 ;
     RECT  20.041 10.824 21.42 11.088 ;
     RECT  20.041 11.088 21.408 11.112 ;
     RECT  20.041 11.112 21.42 11.376 ;
     RECT  20.041 11.376 21.408 11.4 ;
     RECT  20.041 11.4 21.42 11.616 ;
     RECT  20.041 11.616 21.408 11.64 ;
     RECT  20.041 11.64 21.42 11.904 ;
     RECT  20.041 11.904 21.408 11.928 ;
     RECT  20.041 11.928 21.42 12.144 ;
     RECT  20.041 12.144 21.408 12.168 ;
     RECT  20.041 12.168 21.42 12.432 ;
     RECT  20.041 12.432 21.408 12.456 ;
     RECT  20.041 12.456 21.42 12.72 ;
     RECT  20.041 12.72 21.408 12.744 ;
     RECT  20.041 12.744 21.42 12.96 ;
     RECT  20.041 12.96 21.408 12.984 ;
     RECT  20.041 12.984 21.42 13.248 ;
     RECT  20.041 13.248 21.408 13.272 ;
     RECT  20.041 13.272 21.42 13.488 ;
     RECT  20.041 13.488 21.408 13.512 ;
     RECT  20.041 13.512 21.42 13.776 ;
     RECT  20.041 13.776 21.408 13.8 ;
     RECT  20.041 13.8 21.42 14.064 ;
     RECT  20.041 14.064 21.408 14.088 ;
     RECT  20.041 14.088 21.42 14.304 ;
     RECT  20.041 14.304 21.408 14.328 ;
     RECT  20.041 14.328 21.42 14.592 ;
     RECT  20.041 14.592 21.408 14.616 ;
     RECT  20.041 14.616 21.42 14.88 ;
     RECT  20.041 14.88 21.408 14.904 ;
     RECT  20.041 14.904 21.42 15.12 ;
     RECT  20.041 15.12 21.408 15.144 ;
     RECT  20.041 15.144 21.42 15.408 ;
     RECT  20.041 15.408 21.408 15.432 ;
     RECT  20.041 15.432 21.42 15.696 ;
     RECT  20.041 15.696 21.408 15.72 ;
     RECT  20.041 15.72 21.42 15.936 ;
     RECT  20.041 15.936 21.408 15.96 ;
     RECT  20.041 15.96 21.42 16.224 ;
     RECT  20.041 16.224 21.408 16.248 ;
     RECT  20.041 16.248 21.42 16.464 ;
     RECT  20.041 16.464 21.408 16.488 ;
     RECT  20.041 16.488 21.42 16.752 ;
     RECT  20.041 16.752 21.408 16.776 ;
     RECT  20.041 16.776 21.42 17.04 ;
     RECT  20.041 17.04 21.408 17.064 ;
     RECT  20.041 17.064 21.42 17.28 ;
     RECT  20.041 17.28 21.408 17.304 ;
    LAYER M5 ;
     RECT  10.8 1.763 10.812 2.137 ;
     RECT  2.4 2.137 2.52 2.151 ;
     RECT  5.1 2.137 5.22 2.151 ;
     RECT  7.8 2.137 7.92 2.151 ;
     RECT  13.2 2.137 13.32 2.151 ;
     RECT  15.9 2.137 16.02 2.151 ;
     RECT  18.6 2.137 18.72 2.151 ;
     RECT  15.9 2.151 16.212 6.085 ;
     RECT  15.264 6.085 16.212 7.139 ;
     RECT  2.4 2.151 2.712 8.101 ;
     RECT  2.304 8.101 2.712 8.243 ;
     RECT  13.2 2.151 13.512 8.389 ;
     RECT  13.2 8.389 14.472 8.485 ;
     RECT  15.9 7.139 16.212 8.485 ;
     RECT  13.2 8.485 16.212 9.299 ;
     RECT  2.4 8.243 2.712 10.261 ;
     RECT  2.304 10.261 2.712 10.403 ;
     RECT  12.048 8.485 12.072 10.883 ;
     RECT  0.288 10.789 0.312 11.171 ;
     RECT  13.2 9.299 14.472 11.411 ;
     RECT  2.4 10.403 2.712 12.325 ;
     RECT  2.304 12.325 2.712 12.467 ;
     RECT  15.9 9.299 16.212 14.005 ;
     RECT  13.2 11.411 14.376 14.291 ;
     RECT  15.36 14.005 16.212 14.773 ;
     RECT  15.36 14.773 16.92 14.915 ;
     RECT  12.096 11.749 12.12 15.443 ;
     RECT  2.4 12.467 2.712 16.213 ;
     RECT  2.304 16.213 2.712 16.355 ;
     RECT  15.9 14.915 16.92 16.595 ;
     RECT  2.4 16.355 2.712 19.449 ;
     RECT  5.1 2.151 5.412 19.449 ;
     RECT  7.8 2.151 8.112 19.449 ;
     RECT  10.5 2.137 10.812 19.449 ;
     RECT  13.2 14.291 13.512 19.449 ;
     RECT  15.9 16.595 16.212 19.449 ;
     RECT  18.6 2.151 18.912 19.449 ;
     RECT  2.4 19.449 2.52 19.463 ;
     RECT  5.1 19.449 5.22 19.463 ;
     RECT  7.8 19.449 7.92 19.463 ;
     RECT  10.5 19.449 10.62 19.463 ;
     RECT  13.2 19.449 13.32 19.463 ;
     RECT  15.9 19.449 16.02 19.463 ;
     RECT  18.6 19.449 18.72 19.463 ;
     RECT  15.264 7.139 15.9 8.389 ;
     RECT  14.472 8.389 15.9 8.485 ;
     RECT  10.812 8.485 12.048 10.883 ;
     RECT  12.072 8.485 13.2 10.883 ;
     RECT  14.472 9.299 15.9 11.411 ;
     RECT  10.812 10.883 13.2 11.749 ;
     RECT  14.376 11.411 15.9 14.005 ;
     RECT  10.812 11.749 12.096 15.443 ;
     RECT  12.12 11.749 13.2 15.443 ;
     RECT  14.376 14.005 15.36 14.291 ;
  END
END hbfd_rly_48_EW_fc
END LIBRARY
